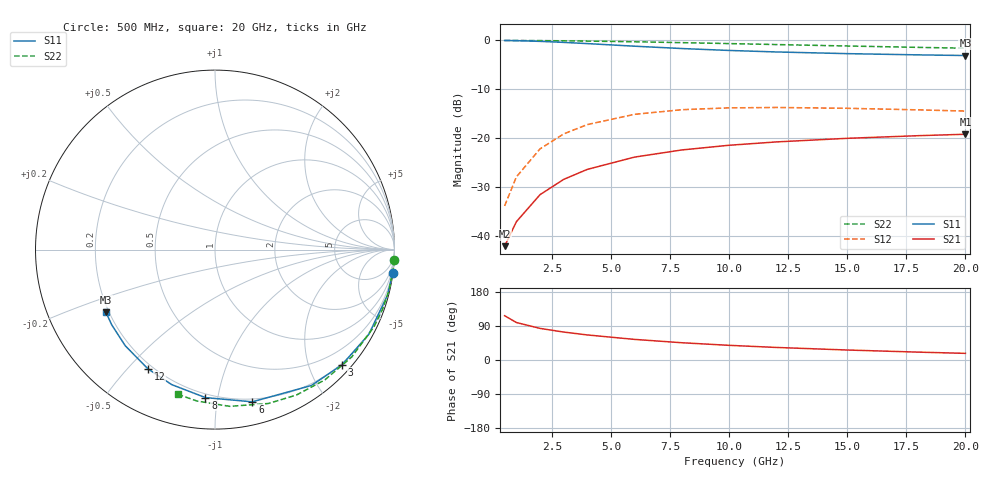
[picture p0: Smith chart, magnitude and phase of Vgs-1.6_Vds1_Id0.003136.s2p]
# Hz S RI R 50
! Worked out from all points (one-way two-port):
!   12 points, 500 MHz to 20 GHz, reference 50 ohm
!   highest |S21| = -19.18 dB at 20 GHz (marker M1); lowest = -42.1 dB at 500 MHz (marker M2)
!   lowest |S11| = -3.1 dB at 20 GHz (marker M3), VSWR 5.69, Z = 9.4 - j12.9 ohm
!   |S11| at or under -10 dB: nowhere
!   |S22| runs from -1.6 to 0.0 dB; largest |S21 - S12| = 0.14
!   S11 on the Smith chart (normalised r, x): 500 MHz: 0, -16; 3 GHz: 0.18, -2.58; 6 GHz: 0.18, -1.26; 8 GHz: 0.18, -0.92; 12 GHz: 0.18, -0.57; 20 GHz: 0.19, -0.26
5e8  0.9904 -0.1277  -0.00357 0.00703  0.00196 0.0202  0.9978 -0.0573
1e9  0.962 -0.2513  -0.00217 0.0139  0.00769 0.0396  0.9921 -0.1143
2e9  0.857 -0.4721  0.00305 0.0263  0.0287 0.0724  0.9698 -0.2258
3e9  0.707 -0.6424  0.0106 0.0365  0.0581 0.0943  0.9338 -0.3317
4e9  0.5365 -0.7574  0.0194 0.044  0.0902 0.1043  0.8857 -0.4304
6e9  0.208 -0.848  0.0374 0.0521  0.1469 0.0964  0.7613 -0.599
8e9  -0.053 -0.8246  0.0532 0.0542  0.1834 0.0687  0.6122 -0.7257
1e10  -0.241 -0.7523  0.0662 0.053  0.2012 0.0366  0.4539 -0.8102
1.2e10  -0.3728 -0.6651  0.0768 0.0501  0.2062 0.00734  0.2976 -0.8574
1.5e10  -0.5002 -0.5356  0.0895 0.0443  0.2006 -0.027  0.0819 -0.8733
1.8e10  -0.5753 -0.4193  0.0993 0.0377  0.1884 -0.0504  -0.1014 -0.8433
2e10  -0.6074 -0.35  0.1048 0.033  0.1794 -0.0615  -0.2048 -0.8071
